VERSION 5.8 ;
BUSBITCHARS "[]" ;
DIVIDERCHAR "/" ;
UNITS
    DATABASE MICRONS 2000 ;
END UNITS

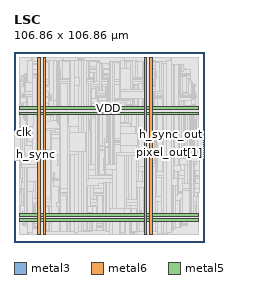
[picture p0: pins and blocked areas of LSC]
MACRO LSC
  FOREIGN LSC 0 0 ;
  CLASS BLOCK ;
  SIZE 106.86 BY 106.86 ;
  PIN clk
    DIRECTION INPUT ;
    USE SIGNAL ;
    PORT
      LAYER metal3 ;
        RECT  0 61.635 0.07 61.705 ;
    END
  END clk
  PIN h_sync
    DIRECTION INPUT ;
    USE SIGNAL ;
    PORT
      LAYER metal3 ;
        RECT  0 49.315 0.07 49.385 ;
    END
  END h_sync
  PIN h_sync_out
    DIRECTION OUTPUT ;
    USE SIGNAL ;
    PORT
      LAYER metal3 ;
        RECT  106.79 60.515 106.86 60.585 ;
    END
  END h_sync_out
  PIN pixel_in[0]
    DIRECTION INPUT ;
    USE SIGNAL ;
    PORT
      LAYER metal3 ;
        RECT  0 47.075 0.07 47.145 ;
    END
  END pixel_in[0]
  PIN pixel_in[1]
    DIRECTION INPUT ;
    USE SIGNAL ;
    PORT
      LAYER metal3 ;
        RECT  0 52.675 0.07 52.745 ;
    END
  END pixel_in[1]
  PIN pixel_in[2]
    DIRECTION INPUT ;
    USE SIGNAL ;
    PORT
      LAYER metal3 ;
        RECT  0 56.035 0.07 56.105 ;
    END
  END pixel_in[2]
  PIN pixel_in[3]
    DIRECTION INPUT ;
    USE SIGNAL ;
    PORT
      LAYER metal3 ;
        RECT  0 51.555 0.07 51.625 ;
    END
  END pixel_in[3]
  PIN pixel_in[4]
    DIRECTION INPUT ;
    USE SIGNAL ;
    PORT
      LAYER metal3 ;
        RECT  0 48.195 0.07 48.265 ;
    END
  END pixel_in[4]
  PIN pixel_in[5]
    DIRECTION INPUT ;
    USE SIGNAL ;
    PORT
      LAYER metal3 ;
        RECT  0 50.435 0.07 50.505 ;
    END
  END pixel_in[5]
  PIN pixel_in[6]
    DIRECTION INPUT ;
    USE SIGNAL ;
    PORT
      LAYER metal3 ;
        RECT  0 54.915 0.07 54.985 ;
    END
  END pixel_in[6]
  PIN pixel_in[7]
    DIRECTION INPUT ;
    USE SIGNAL ;
    PORT
      LAYER metal3 ;
        RECT  0 57.155 0.07 57.225 ;
    END
  END pixel_in[7]
  PIN pixel_in[8]
    DIRECTION INPUT ;
    USE SIGNAL ;
    PORT
      LAYER metal3 ;
        RECT  0 53.795 0.07 53.865 ;
    END
  END pixel_in[8]
  PIN pixel_in[9]
    DIRECTION INPUT ;
    USE SIGNAL ;
    PORT
      LAYER metal3 ;
        RECT  0 45.955 0.07 46.025 ;
    END
  END pixel_in[9]
  PIN pixel_out[0]
    DIRECTION OUTPUT ;
    USE SIGNAL ;
    PORT
      LAYER metal3 ;
        RECT  106.79 57.155 106.86 57.225 ;
    END
  END pixel_out[0]
  PIN pixel_out[1]
    DIRECTION OUTPUT ;
    USE SIGNAL ;
    PORT
      LAYER metal3 ;
        RECT  106.79 54.915 106.86 54.985 ;
    END
  END pixel_out[1]
  PIN pixel_out[2]
    DIRECTION OUTPUT ;
    USE SIGNAL ;
    PORT
      LAYER metal3 ;
        RECT  106.79 51.555 106.86 51.625 ;
    END
  END pixel_out[2]
  PIN pixel_out[3]
    DIRECTION OUTPUT ;
    USE SIGNAL ;
    PORT
      LAYER metal3 ;
        RECT  106.79 50.435 106.86 50.505 ;
    END
  END pixel_out[3]
  PIN pixel_out[4]
    DIRECTION OUTPUT ;
    USE SIGNAL ;
    PORT
      LAYER metal3 ;
        RECT  106.79 58.275 106.86 58.345 ;
    END
  END pixel_out[4]
  PIN pixel_out[5]
    DIRECTION OUTPUT ;
    USE SIGNAL ;
    PORT
      LAYER metal3 ;
        RECT  106.79 59.395 106.86 59.465 ;
    END
  END pixel_out[5]
  PIN pixel_out[6]
    DIRECTION OUTPUT ;
    USE SIGNAL ;
    PORT
      LAYER metal3 ;
        RECT  106.79 49.315 106.86 49.385 ;
    END
  END pixel_out[6]
  PIN pixel_out[7]
    DIRECTION OUTPUT ;
    USE SIGNAL ;
    PORT
      LAYER metal3 ;
        RECT  106.79 48.195 106.86 48.265 ;
    END
  END pixel_out[7]
  PIN pixel_out[8]
    DIRECTION OUTPUT ;
    USE SIGNAL ;
    PORT
      LAYER metal3 ;
        RECT  106.79 56.035 106.86 56.105 ;
    END
  END pixel_out[8]
  PIN pixel_out[9]
    DIRECTION OUTPUT ;
    USE SIGNAL ;
    PORT
      LAYER metal3 ;
        RECT  106.79 53.795 106.86 53.865 ;
    END
  END pixel_out[9]
  PIN resetn
    DIRECTION INPUT ;
    USE SIGNAL ;
    PORT
      LAYER metal3 ;
        RECT  0 59.395 0.07 59.465 ;
    END
  END resetn
  PIN v_sync
    DIRECTION INPUT ;
    USE SIGNAL ;
    PORT
      LAYER metal3 ;
        RECT  0 58.275 0.07 58.345 ;
    END
  END v_sync
  PIN v_sync_out
    DIRECTION OUTPUT ;
    USE SIGNAL ;
    PORT
      LAYER metal3 ;
        RECT  106.79 52.675 106.86 52.745 ;
    END
  END v_sync_out
  PIN valid_in
    DIRECTION INPUT ;
    USE SIGNAL ;
    PORT
      LAYER metal3 ;
        RECT  0 60.515 0.07 60.585 ;
    END
  END valid_in
  PIN valid_out
    DIRECTION OUTPUT ;
    USE SIGNAL ;
    PORT
      LAYER metal3 ;
        RECT  106.79 47.075 106.86 47.145 ;
    END
  END valid_out
  PIN VSS
    DIRECTION INOUT ;
    USE GROUND ;
    PORT
      LAYER metal6 ;
        RECT  73.29 4.16 74.79 103.64 ;
        RECT  13.29 4.16 14.79 103.64 ;
      LAYER metal5 ;
        RECT  3.04 71.45 103.74 72.95 ;
        RECT  3.04 11.45 103.74 12.95 ;
    END
  END VSS
  PIN VDD
    DIRECTION INOUT ;
    USE POWER ;
    PORT
      LAYER metal6 ;
        RECT  76.39 4.16 77.89 103.64 ;
        RECT  16.39 4.16 17.89 103.64 ;
      LAYER metal5 ;
        RECT  3.04 74.55 103.74 76.05 ;
        RECT  3.04 14.55 103.74 16.05 ;
    END
  END VDD
  OBS
    LAYER metal1 ;
     RECT  3.04 4.115 103.74 103.685 ;
    LAYER metal2 ;
     RECT  59.81 4.13 60.27 4.62 ;
     RECT  54.02 4.34 54.09 4.76 ;
     RECT  59.81 4.62 60.74 4.76 ;
     RECT  64.66 4.34 64.73 4.76 ;
     RECT  85.81 4.13 86.27 4.76 ;
     RECT  59.81 4.76 67.58 5.18 ;
     RECT  7.81 4.13 8.27 5.53 ;
     RECT  33.81 4.13 34.27 5.53 ;
     RECT  80.81 4.76 86.27 5.53 ;
     RECT  53.64 4.76 54.09 5.74 ;
     RECT  59.81 5.18 69.1 5.74 ;
     RECT  80.81 5.53 88.37 5.74 ;
     RECT  33.81 5.53 36.37 5.88 ;
     RECT  59.53 5.74 69.1 5.88 ;
     RECT  73.4 5.74 73.47 5.88 ;
     RECT  27.23 5.88 27.3 5.915 ;
     RECT  18.68 5.915 19.13 6.02 ;
     RECT  33.31 5.88 36.37 6.02 ;
     RECT  59.53 5.88 73.47 6.02 ;
     RECT  77.39 5.74 88.37 6.02 ;
     RECT  18.68 6.02 20.08 6.055 ;
     RECT  33.31 6.02 40.03 6.055 ;
     RECT  33.31 6.055 40.22 6.16 ;
     RECT  18.3 6.055 20.08 6.3 ;
     RECT  27.23 5.915 28.44 6.3 ;
     RECT  33.31 6.16 43.45 6.3 ;
     RECT  51.93 5.74 55.42 6.3 ;
     RECT  59.53 6.02 88.37 6.3 ;
     RECT  18.11 6.3 28.44 6.335 ;
     RECT  32.93 6.3 44.59 6.44 ;
     RECT  48.51 6.3 89.24 6.44 ;
     RECT  17.16 6.335 28.44 7.28 ;
     RECT  32.93 6.44 89.43 7.28 ;
     RECT  7.81 5.53 10.37 7.42 ;
     RECT  17.16 7.28 89.43 7.42 ;
     RECT  7.81 7.42 12.67 7.56 ;
     RECT  16.78 7.42 89.43 7.56 ;
     RECT  7.81 7.56 90.57 8.12 ;
     RECT  7.81 8.12 94.18 8.54 ;
     RECT  7.09 8.54 94.18 9.1 ;
     RECT  5.95 9.1 94.18 9.52 ;
     RECT  5 9.52 97.41 10.22 ;
     RECT  4.62 10.22 97.41 12.915 ;
     RECT  3.86 12.915 97.41 14.56 ;
     RECT  3.86 14.56 98.55 14.7 ;
     RECT  3.86 14.7 101.21 14.98 ;
     RECT  3.86 14.98 102.73 15.12 ;
     RECT  3.86 15.12 102.54 20.545 ;
     RECT  4.05 20.545 102.54 22.12 ;
     RECT  4.05 22.12 102.92 27.16 ;
     RECT  3.86 27.16 102.92 27.3 ;
     RECT  3.86 27.3 103.3 27.72 ;
     RECT  3.86 27.72 104.25 29.96 ;
     RECT  3.29 29.96 104.25 30.24 ;
     RECT  4.05 30.24 104.25 35.56 ;
     RECT  3.1 35.56 104.25 37.135 ;
     RECT  2.91 37.135 104.25 49.7 ;
     RECT  2.91 49.7 90.76 50.96 ;
     RECT  2.72 50.96 90.76 51.905 ;
     RECT  2.91 51.905 90.76 53.62 ;
     RECT  94.68 49.7 104.25 53.62 ;
     RECT  2.91 53.62 104.25 53.9 ;
     RECT  3.1 53.9 104.06 56.14 ;
     RECT  3.1 56.14 103.68 56.28 ;
     RECT  3.29 56.28 103.68 56.84 ;
     RECT  3.48 56.84 103.68 58.38 ;
     RECT  3.48 58.38 103.49 60.62 ;
     RECT  3.48 60.62 102.54 63.7 ;
     RECT  3.67 63.7 102.54 71.96 ;
     RECT  4.05 71.96 102.54 72.1 ;
     RECT  5.57 72.1 102.54 76.02 ;
     RECT  5 76.02 102.54 76.3 ;
     RECT  4.43 76.3 102.54 76.825 ;
     RECT  4.43 76.825 102.16 77.42 ;
     RECT  3.67 77.42 102.16 81.48 ;
     RECT  3.67 81.48 102.35 81.9 ;
     RECT  3.67 81.9 102.73 82.04 ;
     RECT  3.67 82.04 102.54 82.46 ;
     RECT  3.67 82.46 102.16 83.58 ;
     RECT  3.67 83.58 101.78 87.5 ;
     RECT  3.67 87.5 101.97 88.48 ;
     RECT  3.67 88.48 101.21 88.62 ;
     RECT  3.67 88.62 100.45 90.44 ;
     RECT  3.67 90.44 99.31 91.28 ;
     RECT  3.86 91.28 99.31 91.84 ;
     RECT  4.05 91.84 99.31 93.38 ;
     RECT  5.76 93.38 99.31 94.045 ;
     RECT  5.95 94.045 99.31 94.5 ;
     RECT  7.81 94.5 99.31 97.16 ;
     RECT  7.81 97.16 96.65 97.3 ;
     RECT  7.81 97.3 96.08 97.58 ;
     RECT  7.81 97.58 95.89 97.72 ;
     RECT  7.81 97.72 95.51 97.86 ;
     RECT  92.21 97.86 95.51 99.96 ;
     RECT  92.21 99.96 93.99 100.1 ;
     RECT  7.81 97.86 88.37 100.38 ;
     RECT  75.11 100.38 88.37 100.485 ;
     RECT  7.81 100.38 70.24 100.625 ;
     RECT  25.9 100.625 70.24 100.66 ;
     RECT  25.9 100.66 49.15 101.045 ;
     RECT  25.9 101.045 48.58 101.08 ;
     RECT  53.83 100.66 69.48 101.36 ;
     RECT  54.4 101.36 69.48 101.5 ;
     RECT  7.81 100.625 21.6 101.64 ;
     RECT  25.9 101.08 48.2 101.64 ;
     RECT  54.4 101.5 55.61 101.64 ;
     RECT  76.82 100.485 88.37 101.64 ;
     RECT  59.81 101.5 69.48 101.78 ;
     RECT  14.31 101.64 21.22 101.885 ;
     RECT  26.66 101.64 48.2 101.885 ;
     RECT  59.81 101.78 69.29 101.885 ;
     RECT  77.2 101.64 79.36 101.885 ;
     RECT  18.87 101.885 21.22 101.92 ;
     RECT  26.66 101.885 47.25 101.92 ;
     RECT  59.81 101.885 68.34 101.92 ;
     RECT  77.2 101.885 78.41 101.92 ;
     RECT  46.04 101.92 46.68 102.025 ;
     RECT  46.04 102.025 46.11 102.06 ;
     RECT  20.2 101.92 21.22 102.165 ;
     RECT  7.81 101.64 10.37 102.27 ;
     RECT  33.81 101.92 39.65 102.27 ;
     RECT  59.81 101.92 62.37 102.27 ;
     RECT  85.81 101.64 88.37 102.27 ;
     RECT  35.91 102.27 39.65 102.445 ;
     RECT  26.66 101.92 28.06 102.865 ;
     RECT  27.23 102.865 28.06 102.9 ;
     RECT  35.91 102.445 39.27 103.145 ;
     RECT  27.61 102.9 28.06 103.285 ;
     RECT  27.61 103.285 27.68 103.32 ;
     RECT  9.91 102.27 10.37 103.67 ;
     RECT  35.91 103.145 36.37 103.67 ;
     RECT  61.91 102.27 62.37 103.67 ;
     RECT  87.91 102.27 88.37 103.67 ;
    LAYER metal3 ;
     RECT  0 55.055 0.035 57.505 ;
     RECT  0.035 45.955 0.34 61.705 ;
     RECT  3.065 35.595 3.445 35.665 ;
     RECT  0.34 45.955 3.445 61.985 ;
     RECT  3.445 35.595 3.635 41.265 ;
     RECT  3.445 44.275 3.635 61.985 ;
     RECT  3.255 30.135 3.825 30.205 ;
     RECT  3.635 91.175 3.825 91.245 ;
     RECT  3.825 91.175 4.015 91.805 ;
     RECT  3.825 28.735 4.205 30.205 ;
     RECT  4.015 14.315 4.395 14.385 ;
     RECT  3.635 77.735 4.395 77.805 ;
     RECT  4.015 91.175 4.395 93.345 ;
     RECT  3.635 35.595 4.585 61.985 ;
     RECT  4.395 13.195 4.965 14.385 ;
     RECT  4.395 76.335 4.965 77.805 ;
     RECT  4.965 70.875 5.155 70.945 ;
     RECT  4.395 90.055 5.155 93.345 ;
     RECT  4.205 25.935 5.345 30.205 ;
     RECT  5.155 69.195 5.345 70.945 ;
     RECT  4.965 83.055 5.345 83.125 ;
     RECT  4.015 20.475 5.535 20.545 ;
     RECT  5.345 25.655 5.535 30.205 ;
     RECT  4.965 76.055 5.535 77.805 ;
     RECT  5.155 87.815 5.535 93.345 ;
     RECT  5.535 20.475 5.725 30.205 ;
     RECT  4.585 33.355 5.725 61.985 ;
     RECT  5.345 69.195 5.725 71.225 ;
     RECT  4.965 9.555 5.915 9.625 ;
     RECT  4.965 13.195 5.915 17.185 ;
     RECT  5.725 20.475 5.915 61.985 ;
     RECT  5.155 65.415 5.915 65.485 ;
     RECT  5.345 83.055 5.915 83.545 ;
     RECT  5.535 87.535 5.915 93.345 ;
     RECT  5.915 83.055 6.185 94.465 ;
     RECT  5.725 68.355 6.295 71.225 ;
     RECT  6.185 82.915 6.485 94.465 ;
     RECT  6.485 82.775 6.745 94.465 ;
     RECT  5.915 9.555 6.865 65.485 ;
     RECT  6.295 68.355 6.865 71.785 ;
     RECT  6.865 9.275 7.055 71.785 ;
     RECT  5.535 76.055 7.055 78.225 ;
     RECT  6.745 81.935 7.055 94.465 ;
     RECT  7.055 8.575 7.245 71.785 ;
     RECT  7.055 76.055 7.245 94.465 ;
     RECT  7.245 8.575 7.81 94.465 ;
     RECT  7.81 4.13 8.27 102.27 ;
     RECT  8.27 5.53 9.91 102.27 ;
     RECT  9.91 5.53 10.37 103.67 ;
     RECT  10.37 8.575 10.615 36.925 ;
     RECT  10.615 8.575 10.805 21.525 ;
     RECT  10.805 8.575 11.755 20.825 ;
     RECT  10.615 24.395 11.945 36.925 ;
     RECT  11.755 14.315 12.135 20.825 ;
     RECT  11.945 24.395 12.135 35.665 ;
     RECT  10.37 39.935 12.895 92.645 ;
     RECT  12.895 55.195 13.085 92.645 ;
     RECT  12.895 39.935 13.275 52.045 ;
     RECT  10.37 97.055 13.325 99.925 ;
     RECT  12.135 14.595 13.465 20.825 ;
     RECT  13.275 48.335 13.465 49.665 ;
     RECT  13.325 97.055 13.515 100.625 ;
     RECT  13.465 14.595 13.655 20.685 ;
     RECT  13.515 96.915 14.085 101.045 ;
     RECT  13.085 81.655 14.225 92.645 ;
     RECT  13.085 61.635 14.795 77.805 ;
     RECT  14.225 91.175 15.035 92.645 ;
     RECT  14.085 95.935 15.035 101.045 ;
     RECT  14.225 81.655 15.175 88.305 ;
     RECT  11.755 8.575 15.415 10.605 ;
     RECT  12.135 24.395 15.605 34.545 ;
     RECT  13.465 49.595 16.175 49.665 ;
     RECT  13.275 39.935 16.365 44.765 ;
     RECT  16.175 49.595 16.365 52.185 ;
     RECT  13.085 55.195 16.365 58.065 ;
     RECT  14.795 61.635 16.365 64.225 ;
     RECT  16.365 39.795 16.555 45.465 ;
     RECT  15.415 8.575 16.745 11.305 ;
     RECT  14.795 67.795 16.885 77.805 ;
     RECT  16.365 48.335 16.965 64.225 ;
     RECT  15.605 24.255 17.125 34.545 ;
     RECT  16.555 37.695 17.125 45.465 ;
     RECT  16.745 7.455 17.315 11.305 ;
     RECT  16.965 52.115 17.455 64.225 ;
     RECT  17.125 24.255 17.505 45.465 ;
     RECT  16.965 48.335 17.505 49.105 ;
     RECT  13.655 14.595 17.645 20.545 ;
     RECT  17.315 7.315 18.265 11.305 ;
     RECT  15.035 91.175 19.405 101.045 ;
     RECT  18.265 6.615 19.595 11.305 ;
     RECT  17.645 14.595 19.595 20.125 ;
     RECT  16.885 74.795 19.595 77.805 ;
     RECT  15.175 81.655 19.595 84.805 ;
     RECT  15.175 87.955 19.66 88.305 ;
     RECT  19.405 91.175 19.66 101.605 ;
     RECT  19.66 87.955 19.785 101.605 ;
     RECT  19.595 6.615 19.975 20.125 ;
     RECT  19.595 74.795 19.975 84.805 ;
     RECT  19.785 87.955 19.975 101.885 ;
     RECT  16.885 67.795 20.305 70.945 ;
     RECT  17.505 24.255 20.355 49.105 ;
     RECT  20.355 23.135 20.545 49.105 ;
     RECT  17.455 52.115 20.545 62.545 ;
     RECT  20.545 23.135 20.875 62.545 ;
     RECT  19.975 6.055 21.305 20.125 ;
     RECT  20.875 23.135 21.305 58.205 ;
     RECT  20.305 68.075 22.255 70.945 ;
     RECT  19.975 74.795 22.255 101.885 ;
     RECT  20.875 61.355 23.395 62.545 ;
     RECT  22.255 68.075 23.965 101.885 ;
     RECT  23.965 67.935 24.155 101.885 ;
     RECT  24.155 67.795 24.725 101.885 ;
     RECT  24.725 66.395 25.105 101.885 ;
     RECT  21.305 6.055 25.485 58.205 ;
     RECT  23.395 61.355 25.485 63.245 ;
     RECT  25.105 66.255 25.485 101.885 ;
     RECT  25.485 6.055 25.815 101.885 ;
     RECT  25.815 6.055 26.005 88.865 ;
     RECT  26.005 6.055 26.195 26.985 ;
     RECT  25.815 91.735 27.525 101.885 ;
     RECT  26.195 6.055 29.665 26.145 ;
     RECT  29.665 6.055 29.855 26.425 ;
     RECT  26.005 29.855 29.855 88.865 ;
     RECT  29.855 6.055 31.185 88.865 ;
     RECT  27.525 91.735 31.185 101.605 ;
     RECT  31.185 6.055 31.565 101.605 ;
     RECT  31.565 6.055 33.81 101.885 ;
     RECT  33.81 4.13 34.27 102.27 ;
     RECT  34.27 5.53 35.91 102.27 ;
     RECT  35.91 5.53 36.37 103.67 ;
     RECT  36.37 6.055 37.975 101.885 ;
     RECT  37.975 6.195 39.305 101.885 ;
     RECT  39.305 6.335 40.635 101.885 ;
     RECT  40.635 6.335 41.205 31.885 ;
     RECT  40.635 92.015 41.775 101.745 ;
     RECT  40.635 35.315 41.965 89.145 ;
     RECT  41.965 35.315 42.155 40.985 ;
     RECT  41.205 6.335 42.395 16.485 ;
     RECT  41.775 92.715 42.725 101.745 ;
     RECT  41.965 43.855 42.915 89.145 ;
     RECT  41.205 19.915 43.105 31.885 ;
     RECT  42.915 89.075 43.105 89.145 ;
     RECT  42.395 6.195 43.485 16.485 ;
     RECT  42.915 43.855 43.865 86.205 ;
     RECT  43.485 6.335 44.295 16.485 ;
     RECT  43.105 19.915 44.295 20.125 ;
     RECT  43.105 24.115 44.625 31.885 ;
     RECT  44.295 89.775 44.675 89.845 ;
     RECT  42.725 92.715 44.675 95.585 ;
     RECT  44.675 89.775 45.195 95.585 ;
     RECT  42.155 37.135 45.625 40.985 ;
     RECT  43.865 43.855 45.625 77.665 ;
     RECT  45.625 37.135 45.955 77.665 ;
     RECT  43.865 80.535 46.005 86.205 ;
     RECT  44.625 24.115 46.145 26.285 ;
     RECT  46.145 24.115 46.195 26.145 ;
     RECT  44.295 6.335 46.335 20.125 ;
     RECT  42.725 98.875 46.335 101.745 ;
     RECT  45.195 90.475 46.385 95.585 ;
     RECT  46.335 98.875 46.385 101.605 ;
     RECT  46.005 80.535 46.525 87.605 ;
     RECT  46.385 90.475 46.525 101.605 ;
     RECT  46.525 80.535 46.715 80.745 ;
     RECT  46.335 11.375 46.955 20.125 ;
     RECT  46.195 23.135 46.955 26.145 ;
     RECT  45.955 37.555 46.955 77.665 ;
     RECT  46.715 80.535 46.955 80.605 ;
     RECT  46.955 37.555 47.285 80.605 ;
     RECT  46.525 84.735 47.475 87.605 ;
     RECT  44.625 29.995 47.525 31.885 ;
     RECT  47.285 37.975 47.855 79.765 ;
     RECT  46.525 90.475 48.045 101.045 ;
     RECT  47.475 85.435 48.095 87.605 ;
     RECT  48.045 90.475 48.095 100.345 ;
     RECT  48.095 85.435 48.995 100.345 ;
     RECT  48.995 92.715 49.565 100.345 ;
     RECT  46.335 6.335 49.615 8.085 ;
     RECT  46.955 11.375 49.615 26.145 ;
     RECT  47.855 54.215 49.755 79.765 ;
     RECT  48.995 85.435 49.755 88.305 ;
     RECT  49.565 92.715 49.755 96.005 ;
     RECT  49.565 100.135 49.945 100.345 ;
     RECT  49.615 6.335 50.185 26.145 ;
     RECT  47.525 29.995 50.185 33.005 ;
     RECT  49.755 92.715 50.325 95.865 ;
     RECT  49.945 100.135 50.325 100.205 ;
     RECT  50.185 6.335 50.565 33.005 ;
     RECT  47.855 37.975 50.755 51.205 ;
     RECT  50.565 6.335 51.275 33.425 ;
     RECT  50.755 37.975 51.275 53.025 ;
     RECT  49.755 85.435 51.515 87.605 ;
     RECT  51.275 37.975 51.655 40.845 ;
     RECT  51.515 84.455 51.705 87.605 ;
     RECT  51.275 6.335 51.895 33.285 ;
     RECT  49.755 56.175 51.895 79.765 ;
     RECT  51.705 83.055 51.895 87.605 ;
     RECT  51.895 56.175 52.655 87.605 ;
     RECT  50.325 92.715 52.655 92.785 ;
     RECT  51.275 43.715 53.415 53.025 ;
     RECT  52.655 56.175 53.415 92.785 ;
     RECT  53.225 100.135 53.415 100.205 ;
     RECT  53.415 43.715 53.605 93.765 ;
     RECT  53.605 43.715 53.795 96.985 ;
     RECT  53.415 99.995 53.795 100.205 ;
     RECT  51.895 5.775 53.985 33.285 ;
     RECT  53.795 43.715 54.365 101.325 ;
     RECT  53.985 4.375 55.125 33.285 ;
     RECT  51.655 37.975 55.125 40.705 ;
     RECT  54.365 43.715 55.645 101.605 ;
     RECT  55.645 43.715 56.215 75.425 ;
     RECT  55.645 78.435 56.405 101.465 ;
     RECT  56.215 43.855 56.595 75.425 ;
     RECT  56.595 43.995 56.785 75.425 ;
     RECT  56.405 91.595 56.785 101.465 ;
     RECT  55.125 4.375 59.115 40.705 ;
     RECT  56.405 78.435 59.305 88.725 ;
     RECT  56.785 91.595 59.305 100.765 ;
     RECT  59.115 4.375 59.81 40.985 ;
     RECT  56.785 43.995 59.81 54.985 ;
     RECT  56.785 58.135 59.81 75.425 ;
     RECT  59.305 78.435 59.81 100.765 ;
     RECT  59.81 4.13 60.27 102.27 ;
     RECT  60.27 4.375 61.91 102.27 ;
     RECT  61.91 4.375 62.37 103.67 ;
     RECT  62.37 4.375 62.675 15.925 ;
     RECT  62.37 18.795 63.245 101.605 ;
     RECT  63.245 18.795 63.435 74.305 ;
     RECT  63.435 24.115 64.385 74.305 ;
     RECT  62.675 4.375 64.765 14.805 ;
     RECT  63.435 18.795 65.525 20.405 ;
     RECT  64.765 5.775 65.765 14.805 ;
     RECT  65.525 18.795 65.765 19.005 ;
     RECT  63.245 77.175 65.765 101.605 ;
     RECT  65.765 5.775 66.095 19.005 ;
     RECT  64.385 24.115 66.285 74.165 ;
     RECT  65.765 77.175 66.665 101.885 ;
     RECT  66.665 77.175 67.045 88.865 ;
     RECT  67.045 77.175 68.045 88.025 ;
     RECT  66.665 92.715 68.375 101.885 ;
     RECT  66.285 24.115 68.945 72.625 ;
     RECT  66.095 5.775 69.135 18.865 ;
     RECT  68.945 24.115 69.185 30.625 ;
     RECT  68.045 77.035 69.375 88.025 ;
     RECT  68.375 92.715 69.515 101.745 ;
     RECT  69.135 5.915 69.565 18.865 ;
     RECT  69.185 22.995 69.565 30.625 ;
     RECT  69.375 76.755 69.755 88.025 ;
     RECT  68.945 34.195 70.085 72.625 ;
     RECT  69.755 75.775 70.135 88.025 ;
     RECT  69.565 5.915 70.845 30.625 ;
     RECT  70.085 34.195 72.02 39.725 ;
     RECT  70.135 75.775 72.035 88.865 ;
     RECT  69.515 92.715 72.035 101.465 ;
     RECT  72.035 75.775 72.745 101.465 ;
     RECT  70.845 5.915 72.935 30.485 ;
     RECT  72.935 5.915 73.365 18.445 ;
     RECT  72.745 90.055 73.885 101.465 ;
     RECT  72.935 21.455 73.935 30.485 ;
     RECT  72.02 34.055 73.935 39.725 ;
     RECT  70.085 42.595 73.935 72.625 ;
     RECT  73.885 98.735 74.455 101.465 ;
     RECT  73.885 90.055 75.215 95.025 ;
     RECT  73.935 21.455 75.405 72.625 ;
     RECT  75.215 90.195 75.785 95.025 ;
     RECT  73.365 5.775 76.025 18.445 ;
     RECT  75.405 21.455 76.025 72.345 ;
     RECT  72.745 75.775 76.025 86.485 ;
     RECT  76.025 5.775 76.735 72.345 ;
     RECT  74.455 99.295 76.785 101.465 ;
     RECT  76.785 99.295 78.065 101.605 ;
     RECT  76.025 75.775 78.305 86.625 ;
     RECT  78.305 75.775 78.875 87.745 ;
     RECT  78.875 75.775 79.015 88.445 ;
     RECT  79.015 84.455 79.065 88.445 ;
     RECT  75.785 91.595 79.065 95.025 ;
     RECT  76.735 5.775 79.55 72.205 ;
     RECT  79.065 84.455 79.635 96.005 ;
     RECT  78.065 99.295 79.635 100.765 ;
     RECT  79.55 25.655 79.965 72.205 ;
     RECT  79.965 39.515 80.395 72.205 ;
     RECT  79.55 5.775 80.775 22.785 ;
     RECT  80.395 39.515 80.775 72.905 ;
     RECT  79.015 75.775 80.775 80.465 ;
     RECT  79.635 84.455 81.915 100.765 ;
     RECT  80.775 4.795 82.865 22.785 ;
     RECT  79.965 25.655 82.865 36.085 ;
     RECT  81.915 84.455 83.005 101.605 ;
     RECT  80.775 39.515 83.66 80.465 ;
     RECT  83.66 39.515 83.78 80.605 ;
     RECT  82.865 4.795 84.195 36.085 ;
     RECT  83.78 39.515 84.195 80.745 ;
     RECT  83.005 84.455 84.195 100.625 ;
     RECT  84.195 4.795 85.81 100.625 ;
     RECT  85.81 4.13 86.27 102.27 ;
     RECT  86.27 5.53 87.91 102.27 ;
     RECT  87.91 5.53 88.37 103.67 ;
     RECT  88.37 6.335 89.275 31.745 ;
     RECT  89.275 6.475 89.465 31.745 ;
     RECT  88.37 35.455 89.465 100.065 ;
     RECT  89.465 35.455 90.415 40.005 ;
     RECT  89.465 42.875 90.415 100.065 ;
     RECT  89.465 7.595 90.605 31.745 ;
     RECT  90.605 26.215 91.745 31.745 ;
     RECT  91.745 28.175 91.985 31.745 ;
     RECT  90.415 35.455 91.985 39.865 ;
     RECT  90.415 43.015 92.315 100.065 ;
     RECT  91.985 28.175 92.695 39.865 ;
     RECT  90.605 8.155 92.885 23.345 ;
     RECT  92.315 43.015 93.075 79.765 ;
     RECT  92.315 82.635 93.075 100.065 ;
     RECT  92.695 39.795 93.265 39.865 ;
     RECT  93.075 43.015 93.315 43.785 ;
     RECT  92.885 14.595 93.505 23.345 ;
     RECT  93.315 42.875 93.505 43.785 ;
     RECT  93.075 83.055 93.645 100.065 ;
     RECT  93.505 42.735 93.695 43.785 ;
     RECT  92.885 8.155 93.835 11.725 ;
     RECT  93.645 95.795 94.025 100.065 ;
     RECT  93.835 8.155 94.215 11.585 ;
     RECT  93.075 46.795 94.405 79.765 ;
     RECT  92.695 28.175 94.785 35.665 ;
     RECT  93.645 83.055 94.785 92.925 ;
     RECT  94.215 9.555 94.975 11.585 ;
     RECT  94.785 32.655 94.975 35.665 ;
     RECT  93.505 14.595 95.025 24.745 ;
     RECT  94.785 28.175 95.025 28.945 ;
     RECT  94.405 46.935 95.165 79.765 ;
     RECT  94.025 95.795 95.165 99.925 ;
     RECT  95.165 46.935 95.545 79.625 ;
     RECT  95.165 96.915 95.545 99.925 ;
     RECT  95.545 46.935 95.735 79.485 ;
     RECT  95.545 96.915 95.925 97.685 ;
     RECT  95.925 96.915 96.115 97.545 ;
     RECT  94.975 32.795 96.165 35.665 ;
     RECT  93.695 39.935 96.165 43.785 ;
     RECT  95.735 46.935 96.305 73.885 ;
     RECT  96.115 96.915 96.685 97.265 ;
     RECT  94.785 84.175 97.065 92.925 ;
     RECT  94.975 9.555 97.445 9.625 ;
     RECT  96.165 32.795 97.495 43.785 ;
     RECT  96.305 46.935 97.495 73.325 ;
     RECT  97.065 84.175 98.015 92.085 ;
     RECT  98.015 84.175 98.065 90.405 ;
     RECT  95.025 14.595 98.585 28.945 ;
     RECT  98.585 15.015 98.825 28.945 ;
     RECT  97.495 32.795 98.825 73.325 ;
     RECT  96.685 96.915 99.155 97.125 ;
     RECT  99.155 97.055 99.345 97.125 ;
     RECT  98.825 15.015 99.395 73.325 ;
     RECT  99.395 15.015 99.775 73.605 ;
     RECT  95.735 76.755 99.775 79.485 ;
     RECT  98.065 83.195 99.775 90.405 ;
     RECT  99.775 15.015 99.915 90.405 ;
     RECT  99.915 15.015 100.105 45.605 ;
     RECT  99.915 49.035 100.105 77.245 ;
     RECT  100.105 49.595 100.485 77.245 ;
     RECT  99.915 80.395 100.485 90.405 ;
     RECT  100.105 15.015 100.865 45.465 ;
     RECT  100.485 49.595 100.865 77.105 ;
     RECT  100.485 80.395 100.865 88.585 ;
     RECT  100.865 15.015 101.055 20.685 ;
     RECT  100.865 49.595 101.245 76.545 ;
     RECT  100.865 87.675 101.245 88.585 ;
     RECT  100.865 25.655 101.435 45.465 ;
     RECT  101.245 71.995 101.435 76.545 ;
     RECT  101.435 25.655 101.625 40.005 ;
     RECT  101.435 74.235 101.625 76.545 ;
     RECT  100.865 80.395 101.625 84.805 ;
     RECT  101.245 87.675 101.625 88.445 ;
     RECT  101.625 32.795 101.815 40.005 ;
     RECT  101.625 81.515 101.815 84.805 ;
     RECT  101.245 63.595 102.005 68.705 ;
     RECT  101.625 88.375 102.005 88.445 ;
     RECT  101.055 15.015 102.195 20.405 ;
     RECT  101.815 32.795 102.195 37.065 ;
     RECT  102.005 63.595 102.195 66.465 ;
     RECT  101.625 75.915 102.195 76.545 ;
     RECT  101.815 81.515 102.195 83.545 ;
     RECT  102.195 15.015 102.385 16.065 ;
     RECT  102.195 75.915 102.385 76.405 ;
     RECT  102.195 81.515 102.385 82.425 ;
     RECT  102.195 63.595 102.575 63.665 ;
     RECT  102.385 81.935 102.575 82.425 ;
     RECT  102.385 15.015 102.765 15.085 ;
     RECT  101.435 43.855 102.765 45.465 ;
     RECT  102.575 81.935 102.765 82.005 ;
     RECT  101.625 25.655 102.955 27.825 ;
     RECT  102.765 45.395 103.145 45.465 ;
     RECT  101.245 49.595 103.195 60.585 ;
     RECT  102.955 27.335 103.335 27.825 ;
     RECT  103.195 49.315 103.385 60.585 ;
     RECT  102.195 32.795 103.525 32.865 ;
     RECT  101.815 39.935 103.525 40.005 ;
     RECT  102.195 36.995 104.095 37.065 ;
     RECT  103.335 27.755 104.285 27.825 ;
     RECT  103.385 47.075 106.825 60.585 ;
    LAYER metal4 ;
     RECT  7.79 4.13 8.29 5.53 ;
     RECT  33.79 4.13 34.29 5.53 ;
     RECT  59.79 4.13 60.29 5.53 ;
     RECT  85.79 4.13 86.29 5.53 ;
     RECT  68.905 7.56 69.045 11.62 ;
     RECT  59.79 5.53 62.39 11.9 ;
     RECT  71.425 13.58 71.565 17.64 ;
     RECT  24.945 13.02 25.085 18.34 ;
     RECT  53.785 11.9 62.39 18.62 ;
     RECT  24.945 18.34 25.365 19.74 ;
     RECT  24.105 19.74 25.365 22.12 ;
     RECT  69.185 22.96 69.325 27.3 ;
     RECT  7.79 5.53 10.39 28.28 ;
     RECT  25.225 22.12 25.365 30.94 ;
     RECT  7.79 28.28 10.805 34.3 ;
     RECT  22.145 30.94 25.365 34.58 ;
     RECT  21.865 34.58 25.365 35.14 ;
     RECT  21.865 35.14 24.525 35.56 ;
     RECT  21.865 35.56 22.565 36.12 ;
     RECT  22.145 36.12 22.565 38.5 ;
     RECT  22.425 38.5 22.565 38.92 ;
     RECT  50.705 39.9 50.845 40.04 ;
     RECT  7.79 34.3 15.845 41.72 ;
     RECT  75.345 41.72 75.485 42.56 ;
     RECT  24.385 42.98 24.525 43.54 ;
     RECT  4.225 41.72 15.845 43.68 ;
     RECT  75.345 42.56 79.405 44.1 ;
     RECT  24.385 43.54 25.645 45.92 ;
     RECT  50.145 40.04 50.845 46.9 ;
     RECT  4.225 43.68 15.005 48.44 ;
     RECT  57.425 18.62 62.39 48.44 ;
     RECT  68.625 42.98 68.765 48.44 ;
     RECT  33.79 5.53 36.39 49.28 ;
     RECT  24.385 45.92 24.525 49.42 ;
     RECT  5.905 48.44 15.005 49.7 ;
     RECT  57.425 48.44 68.765 50.12 ;
     RECT  59.79 50.12 68.765 50.26 ;
     RECT  31.105 49.28 36.39 51.1 ;
     RECT  5.905 49.7 10.39 54.04 ;
     RECT  59.79 50.26 69.045 54.18 ;
     RECT  7.305 54.04 10.39 56.28 ;
     RECT  16.825 49.98 16.965 56.98 ;
     RECT  79.265 44.1 79.405 57.68 ;
     RECT  50.705 46.9 50.845 58.38 ;
     RECT  59.79 54.18 69.325 60.76 ;
     RECT  31.105 51.1 40.205 61.6 ;
     RECT  7.79 56.28 10.39 65.1 ;
     RECT  31.105 61.6 36.39 65.1 ;
     RECT  59.79 60.76 68.205 65.24 ;
     RECT  59.79 65.24 65.405 66.92 ;
     RECT  59.79 66.92 64.845 67.06 ;
     RECT  42.585 62.72 42.725 68.88 ;
     RECT  30.545 65.1 36.39 73.64 ;
     RECT  44.545 69.58 44.685 74.06 ;
     RECT  7.79 65.1 10.805 74.9 ;
     RECT  59.79 67.06 62.39 78.54 ;
     RECT  25.785 75.18 25.925 79.52 ;
     RECT  20.745 79.52 25.925 79.8 ;
     RECT  57.145 78.54 62.39 79.8 ;
     RECT  57.145 79.8 64.285 80.08 ;
     RECT  57.145 80.08 67.925 80.64 ;
     RECT  73.665 79.8 73.805 80.64 ;
     RECT  7.79 74.9 10.39 81.9 ;
     RECT  6.745 81.9 10.39 82.88 ;
     RECT  20.745 79.8 20.885 83.16 ;
     RECT  6.185 82.88 10.39 84.84 ;
     RECT  59.79 80.64 73.805 84.84 ;
     RECT  59.79 84.84 79.405 85.68 ;
     RECT  73.665 85.68 79.405 87.5 ;
     RECT  33.79 73.64 36.39 87.78 ;
     RECT  6.745 84.84 10.39 89.88 ;
     RECT  25.505 88.2 25.645 91.7 ;
     RECT  33.79 87.78 36.845 92.26 ;
     RECT  25.505 91.7 25.925 92.82 ;
     RECT  73.665 87.5 73.805 93.24 ;
     RECT  79.825 91.84 79.965 95.9 ;
     RECT  59.79 85.68 65.685 97.3 ;
     RECT  25.785 92.82 25.925 97.86 ;
     RECT  7.79 89.88 10.39 102.27 ;
     RECT  33.79 92.26 36.39 102.27 ;
     RECT  59.79 97.3 62.39 102.27 ;
     RECT  85.79 5.53 88.39 102.27 ;
     RECT  9.89 102.27 10.39 103.67 ;
     RECT  35.89 102.27 36.39 103.67 ;
     RECT  61.89 102.27 62.39 103.67 ;
     RECT  87.89 102.27 88.39 103.67 ;
    LAYER metal5 ;
     RECT  3.04 11.45 103.74 16.05 ;
     RECT  3.04 71.45 103.74 76.05 ;
    LAYER metal6 ;
     RECT  13.29 4.16 17.89 103.64 ;
     RECT  73.29 4.16 77.89 103.64 ;
  END
END LSC
END LIBRARY
